VERSION 5.7 ;
  NOWIREEXTENSIONATPIN ON ;
  DIVIDERCHAR "/" ;
  BUSBITCHARS "[]" ;
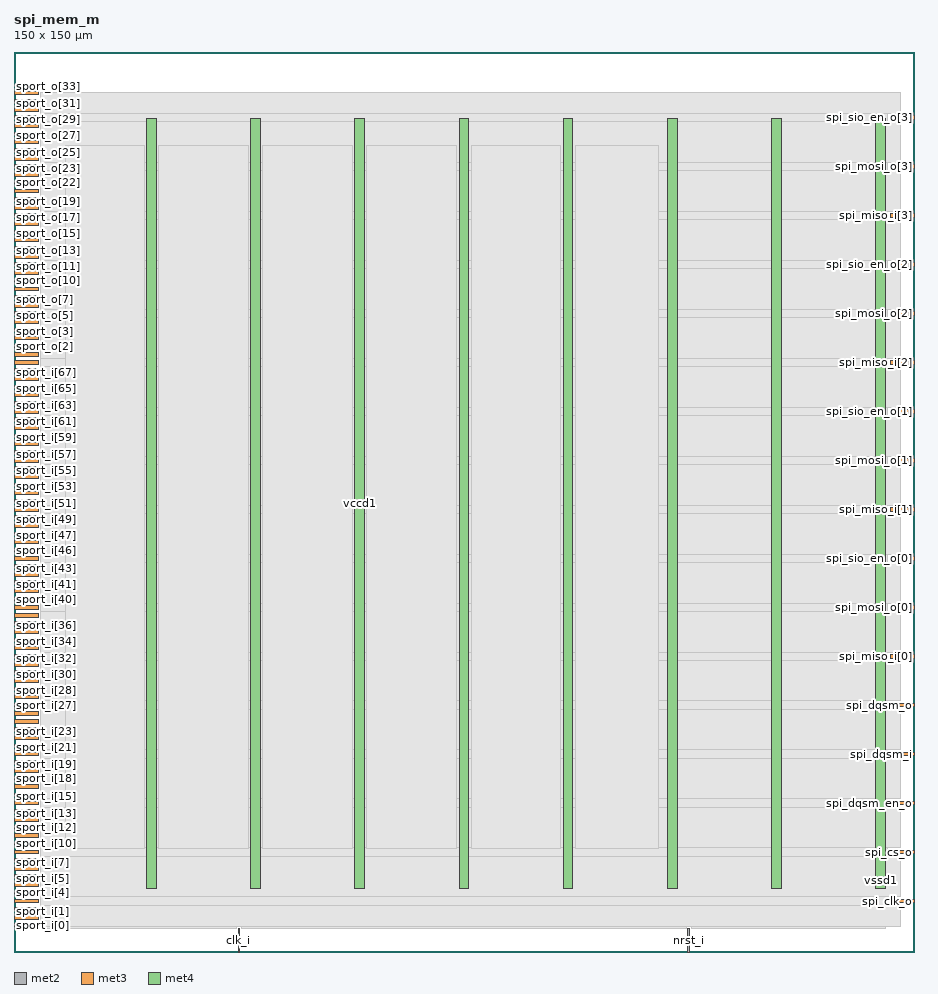
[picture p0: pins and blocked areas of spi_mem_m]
MACRO spi_mem_m
  CLASS BLOCK ;
  FOREIGN spi_mem_m ;
  ORIGIN 0.000 0.000 ;
  SIZE 150.000 BY 150.000 ;
  PIN clk_i
    DIRECTION INPUT ;
    USE SIGNAL ;
    ANTENNAGATEAREA 0.852000 ;
    PORT
      LAYER met2 ;
        RECT 37.350 0.000 37.630 4.000 ;
    END
  END clk_i
  PIN nrst_i
    DIRECTION INPUT ;
    USE SIGNAL ;
    ANTENNAGATEAREA 0.196500 ;
    PORT
      LAYER met2 ;
        RECT 112.330 0.000 112.610 4.000 ;
    END
  END nrst_i
  PIN spi_clk_o
    DIRECTION OUTPUT TRISTATE ;
    USE SIGNAL ;
    ANTENNADIFFAREA 2.673000 ;
    PORT
      LAYER met3 ;
        RECT 146.000 8.200 150.000 8.800 ;
    END
  END spi_clk_o
  PIN spi_cs_o
    DIRECTION OUTPUT TRISTATE ;
    USE SIGNAL ;
    ANTENNADIFFAREA 2.673000 ;
    PORT
      LAYER met3 ;
        RECT 146.000 16.360 150.000 16.960 ;
    END
  END spi_cs_o
  PIN spi_dqsm_en_o
    DIRECTION OUTPUT TRISTATE ;
    USE SIGNAL ;
    ANTENNADIFFAREA 2.673000 ;
    PORT
      LAYER met3 ;
        RECT 146.000 24.520 150.000 25.120 ;
    END
  END spi_dqsm_en_o
  PIN spi_dqsm_i
    DIRECTION INPUT ;
    USE SIGNAL ;
    ANTENNAGATEAREA 0.196500 ;
    PORT
      LAYER met3 ;
        RECT 146.000 32.680 150.000 33.280 ;
    END
  END spi_dqsm_i
  PIN spi_dqsm_o
    DIRECTION OUTPUT TRISTATE ;
    USE SIGNAL ;
    ANTENNADIFFAREA 2.673000 ;
    PORT
      LAYER met3 ;
        RECT 146.000 40.840 150.000 41.440 ;
    END
  END spi_dqsm_o
  PIN spi_miso_i[0]
    DIRECTION INPUT ;
    USE SIGNAL ;
    ANTENNAGATEAREA 0.196500 ;
    PORT
      LAYER met3 ;
        RECT 146.000 49.000 150.000 49.600 ;
    END
  END spi_miso_i[0]
  PIN spi_miso_i[1]
    DIRECTION INPUT ;
    USE SIGNAL ;
    ANTENNAGATEAREA 0.196500 ;
    PORT
      LAYER met3 ;
        RECT 146.000 73.480 150.000 74.080 ;
    END
  END spi_miso_i[1]
  PIN spi_miso_i[2]
    DIRECTION INPUT ;
    USE SIGNAL ;
    ANTENNAGATEAREA 0.196500 ;
    PORT
      LAYER met3 ;
        RECT 146.000 97.960 150.000 98.560 ;
    END
  END spi_miso_i[2]
  PIN spi_miso_i[3]
    DIRECTION INPUT ;
    USE SIGNAL ;
    ANTENNAGATEAREA 0.196500 ;
    PORT
      LAYER met3 ;
        RECT 146.000 122.440 150.000 123.040 ;
    END
  END spi_miso_i[3]
  PIN spi_mosi_o[0]
    DIRECTION OUTPUT TRISTATE ;
    USE SIGNAL ;
    ANTENNADIFFAREA 2.673000 ;
    PORT
      LAYER met3 ;
        RECT 146.000 57.160 150.000 57.760 ;
    END
  END spi_mosi_o[0]
  PIN spi_mosi_o[1]
    DIRECTION OUTPUT TRISTATE ;
    USE SIGNAL ;
    ANTENNADIFFAREA 2.673000 ;
    PORT
      LAYER met3 ;
        RECT 146.000 81.640 150.000 82.240 ;
    END
  END spi_mosi_o[1]
  PIN spi_mosi_o[2]
    DIRECTION OUTPUT TRISTATE ;
    USE SIGNAL ;
    ANTENNADIFFAREA 2.673000 ;
    PORT
      LAYER met3 ;
        RECT 146.000 106.120 150.000 106.720 ;
    END
  END spi_mosi_o[2]
  PIN spi_mosi_o[3]
    DIRECTION OUTPUT TRISTATE ;
    USE SIGNAL ;
    ANTENNADIFFAREA 2.673000 ;
    PORT
      LAYER met3 ;
        RECT 146.000 130.600 150.000 131.200 ;
    END
  END spi_mosi_o[3]
  PIN spi_sio_en_o[0]
    DIRECTION OUTPUT TRISTATE ;
    USE SIGNAL ;
    ANTENNADIFFAREA 2.673000 ;
    PORT
      LAYER met3 ;
        RECT 146.000 65.320 150.000 65.920 ;
    END
  END spi_sio_en_o[0]
  PIN spi_sio_en_o[1]
    DIRECTION OUTPUT TRISTATE ;
    USE SIGNAL ;
    ANTENNADIFFAREA 2.673000 ;
    PORT
      LAYER met3 ;
        RECT 146.000 89.800 150.000 90.400 ;
    END
  END spi_sio_en_o[1]
  PIN spi_sio_en_o[2]
    DIRECTION OUTPUT TRISTATE ;
    USE SIGNAL ;
    ANTENNADIFFAREA 2.673000 ;
    PORT
      LAYER met3 ;
        RECT 146.000 114.280 150.000 114.880 ;
    END
  END spi_sio_en_o[2]
  PIN spi_sio_en_o[3]
    DIRECTION OUTPUT TRISTATE ;
    USE SIGNAL ;
    ANTENNADIFFAREA 2.673000 ;
    PORT
      LAYER met3 ;
        RECT 146.000 138.760 150.000 139.360 ;
    END
  END spi_sio_en_o[3]
  PIN sport_i[0]
    DIRECTION INPUT ;
    USE SIGNAL ;
    ANTENNAGATEAREA 0.196500 ;
    PORT
      LAYER met3 ;
        RECT 0.000 4.120 4.000 4.720 ;
    END
  END sport_i[0]
  PIN sport_i[10]
    DIRECTION INPUT ;
    USE SIGNAL ;
    ANTENNAGATEAREA 0.196500 ;
    PORT
      LAYER met3 ;
        RECT 0.000 17.720 4.000 18.320 ;
    END
  END sport_i[10]
  PIN sport_i[11]
    DIRECTION INPUT ;
    USE SIGNAL ;
    ANTENNAGATEAREA 0.196500 ;
    PORT
      LAYER met3 ;
        RECT 0.000 19.080 4.000 19.680 ;
    END
  END sport_i[11]
  PIN sport_i[12]
    DIRECTION INPUT ;
    USE SIGNAL ;
    ANTENNAGATEAREA 0.196500 ;
    PORT
      LAYER met3 ;
        RECT 0.000 20.440 4.000 21.040 ;
    END
  END sport_i[12]
  PIN sport_i[13]
    DIRECTION INPUT ;
    USE SIGNAL ;
    ANTENNAGATEAREA 0.196500 ;
    PORT
      LAYER met3 ;
        RECT 0.000 21.800 4.000 22.400 ;
    END
  END sport_i[13]
  PIN sport_i[14]
    DIRECTION INPUT ;
    USE SIGNAL ;
    ANTENNAGATEAREA 0.196500 ;
    PORT
      LAYER met3 ;
        RECT 0.000 23.160 4.000 23.760 ;
    END
  END sport_i[14]
  PIN sport_i[15]
    DIRECTION INPUT ;
    USE SIGNAL ;
    ANTENNAGATEAREA 0.196500 ;
    PORT
      LAYER met3 ;
        RECT 0.000 24.520 4.000 25.120 ;
    END
  END sport_i[15]
  PIN sport_i[16]
    DIRECTION INPUT ;
    USE SIGNAL ;
    ANTENNAGATEAREA 0.196500 ;
    PORT
      LAYER met3 ;
        RECT 0.000 25.880 4.000 26.480 ;
    END
  END sport_i[16]
  PIN sport_i[17]
    DIRECTION INPUT ;
    USE SIGNAL ;
    ANTENNAGATEAREA 0.196500 ;
    PORT
      LAYER met3 ;
        RECT 0.000 27.240 4.000 27.840 ;
    END
  END sport_i[17]
  PIN sport_i[18]
    DIRECTION INPUT ;
    USE SIGNAL ;
    ANTENNAGATEAREA 0.196500 ;
    PORT
      LAYER met3 ;
        RECT 0.000 28.600 4.000 29.200 ;
    END
  END sport_i[18]
  PIN sport_i[19]
    DIRECTION INPUT ;
    USE SIGNAL ;
    ANTENNAGATEAREA 0.196500 ;
    PORT
      LAYER met3 ;
        RECT 0.000 29.960 4.000 30.560 ;
    END
  END sport_i[19]
  PIN sport_i[1]
    DIRECTION INPUT ;
    USE SIGNAL ;
    ANTENNAGATEAREA 0.196500 ;
    PORT
      LAYER met3 ;
        RECT 0.000 5.480 4.000 6.080 ;
    END
  END sport_i[1]
  PIN sport_i[20]
    DIRECTION INPUT ;
    USE SIGNAL ;
    ANTENNAGATEAREA 0.196500 ;
    PORT
      LAYER met3 ;
        RECT 0.000 31.320 4.000 31.920 ;
    END
  END sport_i[20]
  PIN sport_i[21]
    DIRECTION INPUT ;
    USE SIGNAL ;
    ANTENNAGATEAREA 0.196500 ;
    PORT
      LAYER met3 ;
        RECT 0.000 32.680 4.000 33.280 ;
    END
  END sport_i[21]
  PIN sport_i[22]
    DIRECTION INPUT ;
    USE SIGNAL ;
    ANTENNAGATEAREA 0.196500 ;
    PORT
      LAYER met3 ;
        RECT 0.000 34.040 4.000 34.640 ;
    END
  END sport_i[22]
  PIN sport_i[23]
    DIRECTION INPUT ;
    USE SIGNAL ;
    ANTENNAGATEAREA 0.196500 ;
    PORT
      LAYER met3 ;
        RECT 0.000 35.400 4.000 36.000 ;
    END
  END sport_i[23]
  PIN sport_i[24]
    DIRECTION INPUT ;
    USE SIGNAL ;
    ANTENNAGATEAREA 0.196500 ;
    PORT
      LAYER met3 ;
        RECT 0.000 36.760 4.000 37.360 ;
    END
  END sport_i[24]
  PIN sport_i[25]
    DIRECTION INPUT ;
    USE SIGNAL ;
    ANTENNAGATEAREA 0.196500 ;
    PORT
      LAYER met3 ;
        RECT 0.000 38.120 4.000 38.720 ;
    END
  END sport_i[25]
  PIN sport_i[26]
    DIRECTION INPUT ;
    USE SIGNAL ;
    ANTENNAGATEAREA 0.196500 ;
    PORT
      LAYER met3 ;
        RECT 0.000 39.480 4.000 40.080 ;
    END
  END sport_i[26]
  PIN sport_i[27]
    DIRECTION INPUT ;
    USE SIGNAL ;
    ANTENNAGATEAREA 0.196500 ;
    PORT
      LAYER met3 ;
        RECT 0.000 40.840 4.000 41.440 ;
    END
  END sport_i[27]
  PIN sport_i[28]
    DIRECTION INPUT ;
    USE SIGNAL ;
    ANTENNAGATEAREA 0.196500 ;
    PORT
      LAYER met3 ;
        RECT 0.000 42.200 4.000 42.800 ;
    END
  END sport_i[28]
  PIN sport_i[29]
    DIRECTION INPUT ;
    USE SIGNAL ;
    ANTENNAGATEAREA 0.196500 ;
    PORT
      LAYER met3 ;
        RECT 0.000 43.560 4.000 44.160 ;
    END
  END sport_i[29]
  PIN sport_i[2]
    DIRECTION INPUT ;
    USE SIGNAL ;
    ANTENNAGATEAREA 0.196500 ;
    PORT
      LAYER met3 ;
        RECT 0.000 6.840 4.000 7.440 ;
    END
  END sport_i[2]
  PIN sport_i[30]
    DIRECTION INPUT ;
    USE SIGNAL ;
    ANTENNAGATEAREA 0.196500 ;
    PORT
      LAYER met3 ;
        RECT 0.000 44.920 4.000 45.520 ;
    END
  END sport_i[30]
  PIN sport_i[31]
    DIRECTION INPUT ;
    USE SIGNAL ;
    ANTENNAGATEAREA 0.196500 ;
    PORT
      LAYER met3 ;
        RECT 0.000 46.280 4.000 46.880 ;
    END
  END sport_i[31]
  PIN sport_i[32]
    DIRECTION INPUT ;
    USE SIGNAL ;
    ANTENNAGATEAREA 0.196500 ;
    PORT
      LAYER met3 ;
        RECT 0.000 47.640 4.000 48.240 ;
    END
  END sport_i[32]
  PIN sport_i[33]
    DIRECTION INPUT ;
    USE SIGNAL ;
    ANTENNAGATEAREA 0.196500 ;
    PORT
      LAYER met3 ;
        RECT 0.000 49.000 4.000 49.600 ;
    END
  END sport_i[33]
  PIN sport_i[34]
    DIRECTION INPUT ;
    USE SIGNAL ;
    ANTENNAGATEAREA 0.196500 ;
    PORT
      LAYER met3 ;
        RECT 0.000 50.360 4.000 50.960 ;
    END
  END sport_i[34]
  PIN sport_i[35]
    DIRECTION INPUT ;
    USE SIGNAL ;
    ANTENNAGATEAREA 0.196500 ;
    PORT
      LAYER met3 ;
        RECT 0.000 51.720 4.000 52.320 ;
    END
  END sport_i[35]
  PIN sport_i[36]
    DIRECTION INPUT ;
    USE SIGNAL ;
    ANTENNAGATEAREA 0.196500 ;
    PORT
      LAYER met3 ;
        RECT 0.000 53.080 4.000 53.680 ;
    END
  END sport_i[36]
  PIN sport_i[37]
    DIRECTION INPUT ;
    USE SIGNAL ;
    ANTENNAGATEAREA 0.196500 ;
    PORT
      LAYER met3 ;
        RECT 0.000 54.440 4.000 55.040 ;
    END
  END sport_i[37]
  PIN sport_i[38]
    DIRECTION INPUT ;
    USE SIGNAL ;
    ANTENNAGATEAREA 0.196500 ;
    PORT
      LAYER met3 ;
        RECT 0.000 55.800 4.000 56.400 ;
    END
  END sport_i[38]
  PIN sport_i[39]
    DIRECTION INPUT ;
    USE SIGNAL ;
    ANTENNAGATEAREA 0.196500 ;
    PORT
      LAYER met3 ;
        RECT 0.000 57.160 4.000 57.760 ;
    END
  END sport_i[39]
  PIN sport_i[3]
    DIRECTION INPUT ;
    USE SIGNAL ;
    ANTENNAGATEAREA 0.196500 ;
    PORT
      LAYER met3 ;
        RECT 0.000 8.200 4.000 8.800 ;
    END
  END sport_i[3]
  PIN sport_i[40]
    DIRECTION INPUT ;
    USE SIGNAL ;
    ANTENNAGATEAREA 0.196500 ;
    PORT
      LAYER met3 ;
        RECT 0.000 58.520 4.000 59.120 ;
    END
  END sport_i[40]
  PIN sport_i[41]
    DIRECTION INPUT ;
    USE SIGNAL ;
    ANTENNAGATEAREA 0.196500 ;
    PORT
      LAYER met3 ;
        RECT 0.000 59.880 4.000 60.480 ;
    END
  END sport_i[41]
  PIN sport_i[42]
    DIRECTION INPUT ;
    USE SIGNAL ;
    ANTENNAGATEAREA 0.196500 ;
    PORT
      LAYER met3 ;
        RECT 0.000 61.240 4.000 61.840 ;
    END
  END sport_i[42]
  PIN sport_i[43]
    DIRECTION INPUT ;
    USE SIGNAL ;
    ANTENNAGATEAREA 0.196500 ;
    PORT
      LAYER met3 ;
        RECT 0.000 62.600 4.000 63.200 ;
    END
  END sport_i[43]
  PIN sport_i[44]
    DIRECTION INPUT ;
    USE SIGNAL ;
    ANTENNAGATEAREA 0.196500 ;
    PORT
      LAYER met3 ;
        RECT 0.000 63.960 4.000 64.560 ;
    END
  END sport_i[44]
  PIN sport_i[45]
    DIRECTION INPUT ;
    USE SIGNAL ;
    ANTENNAGATEAREA 0.196500 ;
    PORT
      LAYER met3 ;
        RECT 0.000 65.320 4.000 65.920 ;
    END
  END sport_i[45]
  PIN sport_i[46]
    DIRECTION INPUT ;
    USE SIGNAL ;
    ANTENNAGATEAREA 0.196500 ;
    PORT
      LAYER met3 ;
        RECT 0.000 66.680 4.000 67.280 ;
    END
  END sport_i[46]
  PIN sport_i[47]
    DIRECTION INPUT ;
    USE SIGNAL ;
    ANTENNAGATEAREA 0.196500 ;
    PORT
      LAYER met3 ;
        RECT 0.000 68.040 4.000 68.640 ;
    END
  END sport_i[47]
  PIN sport_i[48]
    DIRECTION INPUT ;
    USE SIGNAL ;
    ANTENNAGATEAREA 0.196500 ;
    PORT
      LAYER met3 ;
        RECT 0.000 69.400 4.000 70.000 ;
    END
  END sport_i[48]
  PIN sport_i[49]
    DIRECTION INPUT ;
    USE SIGNAL ;
    ANTENNAGATEAREA 0.196500 ;
    PORT
      LAYER met3 ;
        RECT 0.000 70.760 4.000 71.360 ;
    END
  END sport_i[49]
  PIN sport_i[4]
    DIRECTION INPUT ;
    USE SIGNAL ;
    ANTENNAGATEAREA 0.196500 ;
    PORT
      LAYER met3 ;
        RECT 0.000 9.560 4.000 10.160 ;
    END
  END sport_i[4]
  PIN sport_i[50]
    DIRECTION INPUT ;
    USE SIGNAL ;
    ANTENNAGATEAREA 0.196500 ;
    PORT
      LAYER met3 ;
        RECT 0.000 72.120 4.000 72.720 ;
    END
  END sport_i[50]
  PIN sport_i[51]
    DIRECTION INPUT ;
    USE SIGNAL ;
    ANTENNAGATEAREA 0.196500 ;
    PORT
      LAYER met3 ;
        RECT 0.000 73.480 4.000 74.080 ;
    END
  END sport_i[51]
  PIN sport_i[52]
    DIRECTION INPUT ;
    USE SIGNAL ;
    ANTENNAGATEAREA 0.196500 ;
    PORT
      LAYER met3 ;
        RECT 0.000 74.840 4.000 75.440 ;
    END
  END sport_i[52]
  PIN sport_i[53]
    DIRECTION INPUT ;
    USE SIGNAL ;
    ANTENNAGATEAREA 0.196500 ;
    PORT
      LAYER met3 ;
        RECT 0.000 76.200 4.000 76.800 ;
    END
  END sport_i[53]
  PIN sport_i[54]
    DIRECTION INPUT ;
    USE SIGNAL ;
    ANTENNAGATEAREA 0.196500 ;
    PORT
      LAYER met3 ;
        RECT 0.000 77.560 4.000 78.160 ;
    END
  END sport_i[54]
  PIN sport_i[55]
    DIRECTION INPUT ;
    USE SIGNAL ;
    ANTENNAGATEAREA 0.196500 ;
    PORT
      LAYER met3 ;
        RECT 0.000 78.920 4.000 79.520 ;
    END
  END sport_i[55]
  PIN sport_i[56]
    DIRECTION INPUT ;
    USE SIGNAL ;
    ANTENNAGATEAREA 0.196500 ;
    PORT
      LAYER met3 ;
        RECT 0.000 80.280 4.000 80.880 ;
    END
  END sport_i[56]
  PIN sport_i[57]
    DIRECTION INPUT ;
    USE SIGNAL ;
    ANTENNAGATEAREA 0.196500 ;
    PORT
      LAYER met3 ;
        RECT 0.000 81.640 4.000 82.240 ;
    END
  END sport_i[57]
  PIN sport_i[58]
    DIRECTION INPUT ;
    USE SIGNAL ;
    ANTENNAGATEAREA 0.196500 ;
    PORT
      LAYER met3 ;
        RECT 0.000 83.000 4.000 83.600 ;
    END
  END sport_i[58]
  PIN sport_i[59]
    DIRECTION INPUT ;
    USE SIGNAL ;
    ANTENNAGATEAREA 0.196500 ;
    PORT
      LAYER met3 ;
        RECT 0.000 84.360 4.000 84.960 ;
    END
  END sport_i[59]
  PIN sport_i[5]
    DIRECTION INPUT ;
    USE SIGNAL ;
    ANTENNAGATEAREA 0.196500 ;
    PORT
      LAYER met3 ;
        RECT 0.000 10.920 4.000 11.520 ;
    END
  END sport_i[5]
  PIN sport_i[60]
    DIRECTION INPUT ;
    USE SIGNAL ;
    ANTENNAGATEAREA 0.196500 ;
    PORT
      LAYER met3 ;
        RECT 0.000 85.720 4.000 86.320 ;
    END
  END sport_i[60]
  PIN sport_i[61]
    DIRECTION INPUT ;
    USE SIGNAL ;
    ANTENNAGATEAREA 0.196500 ;
    PORT
      LAYER met3 ;
        RECT 0.000 87.080 4.000 87.680 ;
    END
  END sport_i[61]
  PIN sport_i[62]
    DIRECTION INPUT ;
    USE SIGNAL ;
    ANTENNAGATEAREA 0.196500 ;
    PORT
      LAYER met3 ;
        RECT 0.000 88.440 4.000 89.040 ;
    END
  END sport_i[62]
  PIN sport_i[63]
    DIRECTION INPUT ;
    USE SIGNAL ;
    ANTENNAGATEAREA 0.196500 ;
    PORT
      LAYER met3 ;
        RECT 0.000 89.800 4.000 90.400 ;
    END
  END sport_i[63]
  PIN sport_i[64]
    DIRECTION INPUT ;
    USE SIGNAL ;
    ANTENNAGATEAREA 0.196500 ;
    PORT
      LAYER met3 ;
        RECT 0.000 91.160 4.000 91.760 ;
    END
  END sport_i[64]
  PIN sport_i[65]
    DIRECTION INPUT ;
    USE SIGNAL ;
    ANTENNAGATEAREA 0.196500 ;
    PORT
      LAYER met3 ;
        RECT 0.000 92.520 4.000 93.120 ;
    END
  END sport_i[65]
  PIN sport_i[66]
    DIRECTION INPUT ;
    USE SIGNAL ;
    ANTENNAGATEAREA 0.126000 ;
    PORT
      LAYER met3 ;
        RECT 0.000 93.880 4.000 94.480 ;
    END
  END sport_i[66]
  PIN sport_i[67]
    DIRECTION INPUT ;
    USE SIGNAL ;
    ANTENNAGATEAREA 0.213000 ;
    PORT
      LAYER met3 ;
        RECT 0.000 95.240 4.000 95.840 ;
    END
  END sport_i[67]
  PIN sport_i[68]
    DIRECTION INPUT ;
    USE SIGNAL ;
    ANTENNAGATEAREA 0.213000 ;
    PORT
      LAYER met3 ;
        RECT 0.000 96.600 4.000 97.200 ;
    END
  END sport_i[68]
  PIN sport_i[6]
    DIRECTION INPUT ;
    USE SIGNAL ;
    ANTENNAGATEAREA 0.196500 ;
    PORT
      LAYER met3 ;
        RECT 0.000 12.280 4.000 12.880 ;
    END
  END sport_i[6]
  PIN sport_i[7]
    DIRECTION INPUT ;
    USE SIGNAL ;
    ANTENNAGATEAREA 0.196500 ;
    PORT
      LAYER met3 ;
        RECT 0.000 13.640 4.000 14.240 ;
    END
  END sport_i[7]
  PIN sport_i[8]
    DIRECTION INPUT ;
    USE SIGNAL ;
    ANTENNAGATEAREA 0.196500 ;
    PORT
      LAYER met3 ;
        RECT 0.000 15.000 4.000 15.600 ;
    END
  END sport_i[8]
  PIN sport_i[9]
    DIRECTION INPUT ;
    USE SIGNAL ;
    ANTENNAGATEAREA 0.196500 ;
    PORT
      LAYER met3 ;
        RECT 0.000 16.360 4.000 16.960 ;
    END
  END sport_i[9]
  PIN sport_o[0]
    DIRECTION OUTPUT TRISTATE ;
    USE SIGNAL ;
    ANTENNADIFFAREA 2.673000 ;
    PORT
      LAYER met3 ;
        RECT 0.000 97.960 4.000 98.560 ;
    END
  END sport_o[0]
  PIN sport_o[10]
    DIRECTION OUTPUT TRISTATE ;
    USE SIGNAL ;
    ANTENNADIFFAREA 2.673000 ;
    PORT
      LAYER met3 ;
        RECT 0.000 111.560 4.000 112.160 ;
    END
  END sport_o[10]
  PIN sport_o[11]
    DIRECTION OUTPUT TRISTATE ;
    USE SIGNAL ;
    ANTENNADIFFAREA 2.673000 ;
    PORT
      LAYER met3 ;
        RECT 0.000 112.920 4.000 113.520 ;
    END
  END sport_o[11]
  PIN sport_o[12]
    DIRECTION OUTPUT TRISTATE ;
    USE SIGNAL ;
    ANTENNADIFFAREA 2.673000 ;
    PORT
      LAYER met3 ;
        RECT 0.000 114.280 4.000 114.880 ;
    END
  END sport_o[12]
  PIN sport_o[13]
    DIRECTION OUTPUT TRISTATE ;
    USE SIGNAL ;
    ANTENNADIFFAREA 2.673000 ;
    PORT
      LAYER met3 ;
        RECT 0.000 115.640 4.000 116.240 ;
    END
  END sport_o[13]
  PIN sport_o[14]
    DIRECTION OUTPUT TRISTATE ;
    USE SIGNAL ;
    ANTENNADIFFAREA 2.673000 ;
    PORT
      LAYER met3 ;
        RECT 0.000 117.000 4.000 117.600 ;
    END
  END sport_o[14]
  PIN sport_o[15]
    DIRECTION OUTPUT TRISTATE ;
    USE SIGNAL ;
    ANTENNADIFFAREA 2.673000 ;
    PORT
      LAYER met3 ;
        RECT 0.000 118.360 4.000 118.960 ;
    END
  END sport_o[15]
  PIN sport_o[16]
    DIRECTION OUTPUT TRISTATE ;
    USE SIGNAL ;
    ANTENNADIFFAREA 2.673000 ;
    PORT
      LAYER met3 ;
        RECT 0.000 119.720 4.000 120.320 ;
    END
  END sport_o[16]
  PIN sport_o[17]
    DIRECTION OUTPUT TRISTATE ;
    USE SIGNAL ;
    ANTENNADIFFAREA 2.673000 ;
    PORT
      LAYER met3 ;
        RECT 0.000 121.080 4.000 121.680 ;
    END
  END sport_o[17]
  PIN sport_o[18]
    DIRECTION OUTPUT TRISTATE ;
    USE SIGNAL ;
    ANTENNADIFFAREA 2.673000 ;
    PORT
      LAYER met3 ;
        RECT 0.000 122.440 4.000 123.040 ;
    END
  END sport_o[18]
  PIN sport_o[19]
    DIRECTION OUTPUT TRISTATE ;
    USE SIGNAL ;
    ANTENNADIFFAREA 2.673000 ;
    PORT
      LAYER met3 ;
        RECT 0.000 123.800 4.000 124.400 ;
    END
  END sport_o[19]
  PIN sport_o[1]
    DIRECTION OUTPUT TRISTATE ;
    USE SIGNAL ;
    ANTENNADIFFAREA 2.673000 ;
    PORT
      LAYER met3 ;
        RECT 0.000 99.320 4.000 99.920 ;
    END
  END sport_o[1]
  PIN sport_o[20]
    DIRECTION OUTPUT TRISTATE ;
    USE SIGNAL ;
    ANTENNADIFFAREA 2.673000 ;
    PORT
      LAYER met3 ;
        RECT 0.000 125.160 4.000 125.760 ;
    END
  END sport_o[20]
  PIN sport_o[21]
    DIRECTION OUTPUT TRISTATE ;
    USE SIGNAL ;
    ANTENNADIFFAREA 2.673000 ;
    PORT
      LAYER met3 ;
        RECT 0.000 126.520 4.000 127.120 ;
    END
  END sport_o[21]
  PIN sport_o[22]
    DIRECTION OUTPUT TRISTATE ;
    USE SIGNAL ;
    ANTENNADIFFAREA 2.673000 ;
    PORT
      LAYER met3 ;
        RECT 0.000 127.880 4.000 128.480 ;
    END
  END sport_o[22]
  PIN sport_o[23]
    DIRECTION OUTPUT TRISTATE ;
    USE SIGNAL ;
    ANTENNADIFFAREA 2.673000 ;
    PORT
      LAYER met3 ;
        RECT 0.000 129.240 4.000 129.840 ;
    END
  END sport_o[23]
  PIN sport_o[24]
    DIRECTION OUTPUT TRISTATE ;
    USE SIGNAL ;
    ANTENNADIFFAREA 2.673000 ;
    PORT
      LAYER met3 ;
        RECT 0.000 130.600 4.000 131.200 ;
    END
  END sport_o[24]
  PIN sport_o[25]
    DIRECTION OUTPUT TRISTATE ;
    USE SIGNAL ;
    ANTENNADIFFAREA 2.673000 ;
    PORT
      LAYER met3 ;
        RECT 0.000 131.960 4.000 132.560 ;
    END
  END sport_o[25]
  PIN sport_o[26]
    DIRECTION OUTPUT TRISTATE ;
    USE SIGNAL ;
    ANTENNADIFFAREA 2.673000 ;
    PORT
      LAYER met3 ;
        RECT 0.000 133.320 4.000 133.920 ;
    END
  END sport_o[26]
  PIN sport_o[27]
    DIRECTION OUTPUT TRISTATE ;
    USE SIGNAL ;
    ANTENNADIFFAREA 2.673000 ;
    PORT
      LAYER met3 ;
        RECT 0.000 134.680 4.000 135.280 ;
    END
  END sport_o[27]
  PIN sport_o[28]
    DIRECTION OUTPUT TRISTATE ;
    USE SIGNAL ;
    ANTENNADIFFAREA 2.673000 ;
    PORT
      LAYER met3 ;
        RECT 0.000 136.040 4.000 136.640 ;
    END
  END sport_o[28]
  PIN sport_o[29]
    DIRECTION OUTPUT TRISTATE ;
    USE SIGNAL ;
    ANTENNADIFFAREA 2.673000 ;
    PORT
      LAYER met3 ;
        RECT 0.000 137.400 4.000 138.000 ;
    END
  END sport_o[29]
  PIN sport_o[2]
    DIRECTION OUTPUT TRISTATE ;
    USE SIGNAL ;
    ANTENNADIFFAREA 2.673000 ;
    PORT
      LAYER met3 ;
        RECT 0.000 100.680 4.000 101.280 ;
    END
  END sport_o[2]
  PIN sport_o[30]
    DIRECTION OUTPUT TRISTATE ;
    USE SIGNAL ;
    ANTENNADIFFAREA 2.673000 ;
    PORT
      LAYER met3 ;
        RECT 0.000 138.760 4.000 139.360 ;
    END
  END sport_o[30]
  PIN sport_o[31]
    DIRECTION OUTPUT TRISTATE ;
    USE SIGNAL ;
    ANTENNADIFFAREA 2.673000 ;
    PORT
      LAYER met3 ;
        RECT 0.000 140.120 4.000 140.720 ;
    END
  END sport_o[31]
  PIN sport_o[32]
    DIRECTION OUTPUT TRISTATE ;
    USE SIGNAL ;
    ANTENNADIFFAREA 2.673000 ;
    PORT
      LAYER met3 ;
        RECT 0.000 141.480 4.000 142.080 ;
    END
  END sport_o[32]
  PIN sport_o[33]
    DIRECTION OUTPUT TRISTATE ;
    USE SIGNAL ;
    ANTENNADIFFAREA 2.673000 ;
    PORT
      LAYER met3 ;
        RECT 0.000 142.840 4.000 143.440 ;
    END
  END sport_o[33]
  PIN sport_o[3]
    DIRECTION OUTPUT TRISTATE ;
    USE SIGNAL ;
    ANTENNADIFFAREA 2.673000 ;
    PORT
      LAYER met3 ;
        RECT 0.000 102.040 4.000 102.640 ;
    END
  END sport_o[3]
  PIN sport_o[4]
    DIRECTION OUTPUT TRISTATE ;
    USE SIGNAL ;
    ANTENNADIFFAREA 2.673000 ;
    PORT
      LAYER met3 ;
        RECT 0.000 103.400 4.000 104.000 ;
    END
  END sport_o[4]
  PIN sport_o[5]
    DIRECTION OUTPUT TRISTATE ;
    USE SIGNAL ;
    ANTENNADIFFAREA 2.673000 ;
    PORT
      LAYER met3 ;
        RECT 0.000 104.760 4.000 105.360 ;
    END
  END sport_o[5]
  PIN sport_o[6]
    DIRECTION OUTPUT TRISTATE ;
    USE SIGNAL ;
    ANTENNADIFFAREA 2.673000 ;
    PORT
      LAYER met3 ;
        RECT 0.000 106.120 4.000 106.720 ;
    END
  END sport_o[6]
  PIN sport_o[7]
    DIRECTION OUTPUT TRISTATE ;
    USE SIGNAL ;
    ANTENNADIFFAREA 2.673000 ;
    PORT
      LAYER met3 ;
        RECT 0.000 107.480 4.000 108.080 ;
    END
  END sport_o[7]
  PIN sport_o[8]
    DIRECTION OUTPUT TRISTATE ;
    USE SIGNAL ;
    ANTENNADIFFAREA 2.673000 ;
    PORT
      LAYER met3 ;
        RECT 0.000 108.840 4.000 109.440 ;
    END
  END sport_o[8]
  PIN sport_o[9]
    DIRECTION OUTPUT TRISTATE ;
    USE SIGNAL ;
    ANTENNADIFFAREA 2.673000 ;
    PORT
      LAYER met3 ;
        RECT 0.000 110.200 4.000 110.800 ;
    END
  END sport_o[9]
  PIN vccd1
    DIRECTION INOUT ;
    USE POWER ;
    PORT
      LAYER met4 ;
        RECT 22.085 10.640 23.685 138.960 ;
    END
    PORT
      LAYER met4 ;
        RECT 56.815 10.640 58.415 138.960 ;
    END
    PORT
      LAYER met4 ;
        RECT 91.545 10.640 93.145 138.960 ;
    END
    PORT
      LAYER met4 ;
        RECT 126.275 10.640 127.875 138.960 ;
    END
  END vccd1
  PIN vssd1
    DIRECTION INOUT ;
    USE GROUND ;
    PORT
      LAYER met4 ;
        RECT 39.450 10.640 41.050 138.960 ;
    END
    PORT
      LAYER met4 ;
        RECT 74.180 10.640 75.780 138.960 ;
    END
    PORT
      LAYER met4 ;
        RECT 108.910 10.640 110.510 138.960 ;
    END
    PORT
      LAYER met4 ;
        RECT 143.640 10.640 145.240 138.960 ;
    END
  END vssd1
  OBS
      LAYER li1 ;
        RECT 5.520 10.795 144.440 138.805 ;
      LAYER met1 ;
        RECT 4.670 7.860 145.240 141.060 ;
      LAYER met2 ;
        RECT 4.690 4.280 145.210 143.325 ;
        RECT 4.690 4.000 37.070 4.280 ;
        RECT 37.910 4.000 112.050 4.280 ;
        RECT 112.890 4.000 145.210 4.280 ;
      LAYER met3 ;
        RECT 4.400 139.760 147.810 143.305 ;
        RECT 4.400 138.360 145.600 139.760 ;
        RECT 4.400 131.600 147.810 138.360 ;
        RECT 4.400 130.200 145.600 131.600 ;
        RECT 4.400 123.440 147.810 130.200 ;
        RECT 4.400 122.040 145.600 123.440 ;
        RECT 4.400 115.280 147.810 122.040 ;
        RECT 4.400 113.880 145.600 115.280 ;
        RECT 4.400 107.120 147.810 113.880 ;
        RECT 4.400 105.720 145.600 107.120 ;
        RECT 4.400 98.960 147.810 105.720 ;
        RECT 4.400 97.560 145.600 98.960 ;
        RECT 4.400 90.800 147.810 97.560 ;
        RECT 4.400 89.400 145.600 90.800 ;
        RECT 4.400 82.640 147.810 89.400 ;
        RECT 4.400 81.240 145.600 82.640 ;
        RECT 4.400 74.480 147.810 81.240 ;
        RECT 4.400 73.080 145.600 74.480 ;
        RECT 4.400 66.320 147.810 73.080 ;
        RECT 4.400 64.920 145.600 66.320 ;
        RECT 4.400 58.160 147.810 64.920 ;
        RECT 4.400 56.760 145.600 58.160 ;
        RECT 4.400 50.000 147.810 56.760 ;
        RECT 4.400 48.600 145.600 50.000 ;
        RECT 4.400 41.840 147.810 48.600 ;
        RECT 4.400 40.440 145.600 41.840 ;
        RECT 4.400 33.680 147.810 40.440 ;
        RECT 4.400 32.280 145.600 33.680 ;
        RECT 4.400 25.520 147.810 32.280 ;
        RECT 4.400 24.120 145.600 25.520 ;
        RECT 4.400 17.360 147.810 24.120 ;
        RECT 4.400 15.960 145.600 17.360 ;
        RECT 4.400 9.200 147.810 15.960 ;
        RECT 4.400 7.800 145.600 9.200 ;
        RECT 4.400 4.255 147.810 7.800 ;
      LAYER met4 ;
        RECT 8.575 17.175 21.685 134.465 ;
        RECT 24.085 17.175 39.050 134.465 ;
        RECT 41.450 17.175 56.415 134.465 ;
        RECT 58.815 17.175 73.780 134.465 ;
        RECT 76.180 17.175 91.145 134.465 ;
        RECT 93.545 17.175 107.345 134.465 ;
  END
END spi_mem_m
END LIBRARY

